VERSION 5.8 ;
BUSBITCHARS "[]" ;
DIVIDERCHAR "/" ;
UNITS
  DATABASE MICRONS 1000 ;
END UNITS
MANUFACTURINGGRID 0.005 ;

# Synthetic stack for the mask-balance pre-screen tests. Every name and value is invented. M1 and
# M2 have two masks, M3 one.

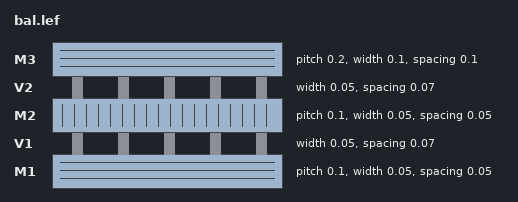
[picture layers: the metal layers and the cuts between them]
LAYER M1
  TYPE ROUTING ;
  DIRECTION HORIZONTAL ;
  PITCH 0.1 ;
  WIDTH 0.05 ;
  SPACING 0.05 ;
  MASK 2 ;
END M1

LAYER V1
  TYPE CUT ;
  WIDTH 0.05 ;
  SPACING 0.07 ;
END V1

LAYER M2
  TYPE ROUTING ;
  DIRECTION VERTICAL ;
  PITCH 0.1 ;
  WIDTH 0.05 ;
  SPACING 0.05 ;
  MASK 2 ;
END M2

LAYER V2
  TYPE CUT ;
  WIDTH 0.05 ;
  SPACING 0.07 ;
END V2

LAYER M3
  TYPE ROUTING ;
  DIRECTION HORIZONTAL ;
  PITCH 0.2 ;
  WIDTH 0.1 ;
  SPACING 0.1 ;
END M3

# A block whose only metal is a 2 x 2 obstruction on M1: uncoloured cell metal.
MACRO blk
  CLASS BLOCK ;
  ORIGIN 0 0 ;
  SIZE 2 BY 2 ;
  OBS
    LAYER M1 ;
      RECT 0 0 2 2 ;
  END
END blk

END LIBRARY
